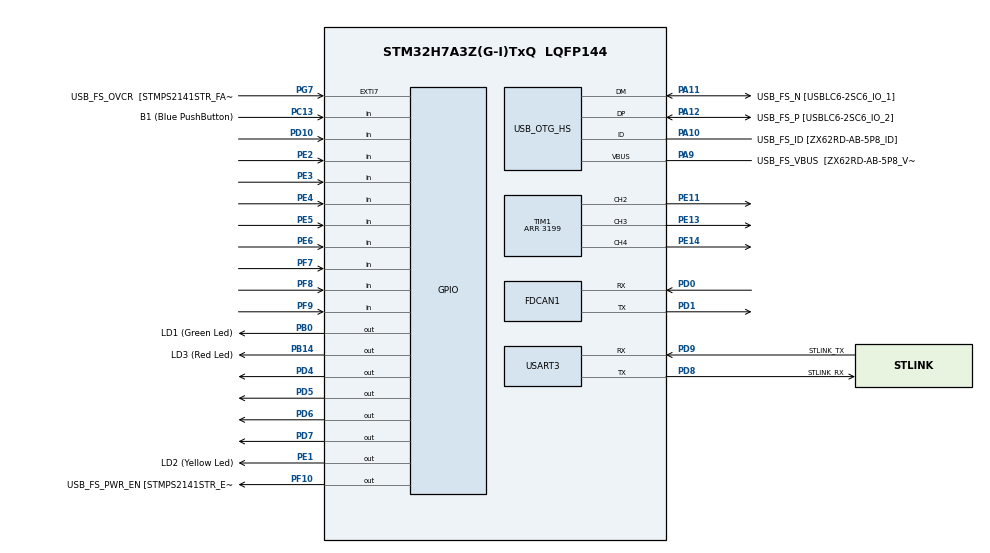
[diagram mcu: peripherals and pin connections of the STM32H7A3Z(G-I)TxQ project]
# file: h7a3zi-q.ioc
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Dma.Request0=USART3_RX
Dma.USART3_RX.0.Direction=DMA_PERIPH_TO_MEMORY
Dma.USART3_RX.0.EventEnable=DISABLE
Dma.USART3_RX.0.FIFOMode=DMA_FIFOMODE_DISABLE
Dma.USART3_RX.0.Instance=DMA1_Stream0
Dma.USART3_RX.0.MemDataAlignment=DMA_MDATAALIGN_BYTE
Dma.USART3_RX.0.MemInc=DMA_MINC_ENABLE
Dma.USART3_RX.0.Mode=DMA_CIRCULAR
Dma.USART3_RX.0.PeriphDataAlignment=DMA_PDATAALIGN_BYTE
Dma.USART3_RX.0.PeriphInc=DMA_PINC_DISABLE
Dma.USART3_RX.0.Polarity=HAL_DMAMUX_REQ_GEN_RISING
Dma.USART3_RX.0.Priority=DMA_PRIORITY_LOW
Dma.USART3_RX.0.RequestNumber=1
Dma.USART3_RX.0.SignalID=NONE
Dma.USART3_RX.0.SyncEnable=DISABLE
Dma.USART3_RX.0.SyncPolarity=HAL_DMAMUX_SYNC_NO_EVENT
Dma.USART3_RX.0.SyncRequestNumber=1
Dma.USART3_RX.0.SyncSignalID=NONE
FDCAN1.AutoRetransmission=ENABLE
FDCAN1.CalculateBaudRateNominal=1000000
FDCAN1.CalculateTimeBitNominal=1000
FDCAN1.CalculateTimeQuantumNominal=20.0
FDCAN1.DataPrescaler=2
FDCAN1.DataSyncJumpWidth=12
FDCAN1.DataTimeSeg1=12
FDCAN1.DataTimeSeg2=12
FDCAN1.ExtFiltersNbr=0
FDCAN1.FrameFormat=FDCAN_FRAME_CLASSIC
FDCAN1.NominalPrescaler=1
FDCAN1.NominalSyncJumpWidth=14
FDCAN1.NominalTimeSeg1=35
FDCAN1.NominalTimeSeg2=14
FDCAN1.RxFifo0ElmtSize=FDCAN_DATA_BYTES_8
FDCAN1.RxFifo0ElmtsNbr=32
FDCAN1.StdFiltersNbr=0
FDCAN1.TransmitPause=ENABLE
FDCAN1.TxFifoQueueElmtsNbr=32
Mcu.Family=STM32H7
Mcu.Name=STM32H7A3Z(G-I)TxQ
Mcu.Package=LQFP144
NVIC.DMA1_Stream0_IRQn=true\:0\:0\:false\:false\:true\:false\:true\:true
NVIC.FDCAN1_IT0_IRQn=true\:0\:0\:false\:false\:true\:true\:true\:true
NVIC.PriorityGroup=NVIC_PRIORITYGROUP_4
NVIC.TIM6_DAC_IRQn=true\:15\:0\:false\:false\:true\:false\:true\:true
NVIC.TimeBase=TIM6_DAC_IRQn
NVIC.TimeBaseIP=TIM6
NVIC.USART3_IRQn=true\:0\:0\:false\:false\:true\:true\:true\:true
PA10.GPIO_Label=USB_FS_ID [ZX62RD-AB-5P8_ID]
PA10.Mode=OTG/Dual-Role-Device-FS
PA10.Signal=USB_OTG_HS_ID
PA11.GPIO_Label=USB_FS_N [USBLC6-2SC6_IO_1]
PA11.Mode=OTG/Dual-Role-Device-FS
PA11.Signal=USB_OTG_HS_DM
PA12.GPIO_Label=USB_FS_P [USBLC6-2SC6_IO_2]
PA12.Mode=OTG/Dual-Role-Device-FS
PA12.Signal=USB_OTG_HS_DP
PA9.GPIO_Label=USB_FS_VBUS  [ZX62RD-AB-5P8_VBUS]
PA9.Mode=Activate_VBUS_FS
PA9.Signal=USB_OTG_HS_VBUS
PB0.GPIO_Label=LD1 (Green Led)
PB0.Signal=GPIO_Output
PB14.GPIO_Label=LD3 (Red Led)
PB14.Signal=GPIO_Output
PC13.GPIO_Label=B1 (Blue PushButton)
PC13.Signal=GPIO_Input
PC14-OSC32_IN.GPIO_Label=OSC32_IN
PC14-OSC32_IN.Mode=LSE-External-Oscillator
PC14-OSC32_IN.Signal=RCC_OSC32_IN
PC15-OSC32_OUT.GPIO_Label=OSC32_OUT
PC15-OSC32_OUT.Mode=LSE-External-Oscillator
PC15-OSC32_OUT.Signal=RCC_OSC32_OUT
PD0.Mode=FDCAN_Activate
PD0.Signal=FDCAN1_RX
PD1.Mode=FDCAN_Activate
PD1.Signal=FDCAN1_TX
PD10.GPIO_PuPd=GPIO_PULLDOWN
PD10.Signal=GPIO_Input
PD4.Signal=GPIO_Output
PD5.Signal=GPIO_Output
PD6.Signal=GPIO_Output
PD7.Signal=GPIO_Output
PD8.GPIO_Label=STLINK_RX
PD8.Mode=Asynchronous
PD8.Signal=USART3_TX
PD9.GPIO_Label=STLINK_TX
PD9.Mode=Asynchronous
PD9.Signal=USART3_RX
PE1.GPIO_Label=LD2 (Yellow Led)
PE1.Signal=GPIO_Output
PE11.GPIO_PuPd=GPIO_PULLDOWN
PE11.Signal=S_TIM1_CH2
PE13.GPIO_PuPd=GPIO_PULLDOWN
PE13.Signal=S_TIM1_CH3
PE14.GPIO_PuPd=GPIO_PULLDOWN
PE14.Signal=S_TIM1_CH4
PE2.GPIO_PuPd=GPIO_PULLDOWN
PE2.Signal=GPIO_Input
PE3.GPIO_PuPd=GPIO_PULLDOWN
PE3.Signal=GPIO_Input
PE4.GPIO_PuPd=GPIO_PULLDOWN
PE4.Signal=GPIO_Input
PE5.GPIO_PuPd=GPIO_PULLDOWN
PE5.Signal=GPIO_Input
PE6.GPIO_PuPd=GPIO_PULLDOWN
PE6.Signal=GPIO_Input
PF10.GPIO_Label=USB_FS_PWR_EN [STMPS2141STR_EN]
PF10.Signal=GPIO_Output
PF7.GPIO_PuPd=GPIO_PULLDOWN
PF7.Signal=GPIO_Input
PF8.GPIO_PuPd=GPIO_PULLDOWN
PF8.Signal=GPIO_Input
PF9.GPIO_PuPd=GPIO_PULLDOWN
PF9.Signal=GPIO_Input
PG7.GPIO_Label=USB_FS_OVCR  [STMPS2141STR_FAULT]
PG7.Signal=GPXTI7
PH0-OSC_IN.GPIO_Label=PH0-MCU
PH0-OSC_IN.Mode=HSE-External-Oscillator
PH0-OSC_IN.Signal=RCC_OSC_IN
PH1-OSC_OUT.GPIO_Label=PH1-MCU
PH1-OSC_OUT.Mode=HSE-External-Oscillator
PH1-OSC_OUT.Signal=RCC_OSC_OUT
ProjectManager.HeapSize=0x200
ProjectManager.StackSize=0x400
ProjectManager.TargetToolchain=STM32CubeIDE
RCC.ADCFreq_Value=129000000
RCC.APB1Freq_Value=64000000
RCC.APB2Freq_Value=64000000
RCC.APB3Freq_Value=64000000
RCC.APB4Freq_Value=64000000
RCC.CortexFreq_Value=64000000
RCC.DIVM1=4
RCC.DIVM3=1
RCC.DIVN1=9
RCC.DIVN3=24
RCC.DIVQ1=3
RCC.HCLKFreq_Value=64000000
RCC.HSE_VALUE=8000000
RCC.PLLFRACN=3072
RCC.PWR_Regulator_Voltage_Scale=PWR_REGULATOR_VOLTAGE_SCALE0
RCC.SYSCLKFreq_VALUE=64000000
RCC.SupplySource=PWR_DIRECT_SMPS_SUPPLY
RCC.USBCLockSelection=RCC_USBCLKSOURCE_HSI48
RCC.USBFreq_Value=48000000
SH.S_TIM1_CH2.0=TIM1_CH2,PWM Generation2 CH2
SH.S_TIM1_CH3.0=TIM1_CH3,PWM Generation3 CH3
SH.S_TIM1_CH4.0=TIM1_CH4,PWM Generation4 CH4
TIM1.Channel-PWM\ Generation2\ CH2=TIM_CHANNEL_2
TIM1.Channel-PWM\ Generation3\ CH3=TIM_CHANNEL_3
TIM1.Channel-PWM\ Generation4\ CH4=TIM_CHANNEL_4
TIM1.Period=3199
USART3.VirtualMode-Asynchronous=VM_ASYNC
VP_SYS_VS_tim6.Mode=TIM6
board=NUCLEO-H7A3ZI-Q

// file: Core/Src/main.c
/* USER CODE BEGIN Header */
/**
  ******************************************************************************
  * @file           : main.c
  * @brief          : Main program body
  ******************************************************************************
  * @attention
  *
  * Copyright (c) 2023 STMicroelectronics.
  * All rights reserved.
  *
  * This software is licensed under terms that can be found in the LICENSE file
  * in the root directory of this software component.
  * If no LICENSE file comes with this software, it is provided AS-IS.
  *
  ******************************************************************************
  */
/* USER CODE END Header */
#include "main.h"

/* USER CODE BEGIN Includes */

#include <Periph_Switch.h>
#include <Periph_UartRingBuf.h>
#include <Periph_Solenoid.h>
#include <Manager_Motor.h>
#include <Manager_HMI.h>
#include <Manager_Movement.h>
#include <Manager_Security.h>
#include <Manager_Error.h>

/* USER CODE END Includes */

FDCAN_HandleTypeDef hfdcan1;

TIM_HandleTypeDef htim1;

UART_HandleTypeDef huart3;
DMA_HandleTypeDef hdma_usart3_rx;

void SystemClock_Config(void);
static void MX_GPIO_Init(void);
static void MX_DMA_Init(void);
static void MX_USB_OTG_HS_USB_Init(void);
static void MX_FDCAN1_Init(void);
static void MX_USART3_UART_Init(void);
static void MX_TIM1_Init(void);

int main(void)
{

  /* MCU Configuration--------------------------------------------------------*/

  /* Reset of all peripherals, Initializes the Flash interface and the Systick. */
  HAL_Init();

  /* Configure the system clock */
  SystemClock_Config();

  /* Initialize all configured peripherals */
  MX_GPIO_Init();
  MX_DMA_Init();
  MX_USB_OTG_HS_USB_Init();
  MX_FDCAN1_Init();
  MX_USART3_UART_Init();
  MX_TIM1_Init();

  /* Infinite loop */
  /* USER CODE BEGIN WHILE */

    ManagerError_Init();
	ManagerMotor_Init();
	ManagerHMI_Init();
	ManagerMovement_Init();
	ManagerSecurity_Init();
	PeriphSolenoid_Init();

  while (1)
  {
	PeriphUartRingBuf_Task();
	PeriphSwitch_Task();

	ManagerMotor_Task();
	ManagerHMI_Task();
	ManagerMovement_Task();
	ManagerSecurity_Task();

    /* USER CODE END WHILE */

  }
}

void SystemClock_Config(void)
{
  RCC_OscInitTypeDef RCC_OscInitStruct = {0};
  RCC_ClkInitTypeDef RCC_ClkInitStruct = {0};

  /*AXI clock gating */
  RCC->CKGAENR = 0xFFFFFFFF;

  /** Supply configuration update enable
  */
  HAL_PWREx_ConfigSupply(PWR_DIRECT_SMPS_SUPPLY);

  /** Configure the main internal regulator output voltage
  */
  __HAL_PWR_VOLTAGESCALING_CONFIG(PWR_REGULATOR_VOLTAGE_SCALE0);

  while(!__HAL_PWR_GET_FLAG(PWR_FLAG_VOSRDY)) {}

  /** Initializes the RCC Oscillators according to the specified parameters
  * in the RCC_OscInitTypeDef structure.
  */
  RCC_OscInitStruct.OscillatorType = RCC_OSCILLATORTYPE_HSI48|RCC_OSCILLATORTYPE_HSI;
  RCC_OscInitStruct.HSIState = RCC_HSI_DIV1;
  RCC_OscInitStruct.HSICalibrationValue = 64;
  RCC_OscInitStruct.HSI48State = RCC_HSI48_ON;
  RCC_OscInitStruct.PLL.PLLState = RCC_PLL_ON;
  RCC_OscInitStruct.PLL.PLLSource = RCC_PLLSOURCE_HSI;
  RCC_OscInitStruct.PLL.PLLM = 4;
  RCC_OscInitStruct.PLL.PLLN = 9;
  RCC_OscInitStruct.PLL.PLLP = 2;
  RCC_OscInitStruct.PLL.PLLQ = 3;
  RCC_OscInitStruct.PLL.PLLR = 2;
  RCC_OscInitStruct.PLL.PLLRGE = RCC_PLL1VCIRANGE_3;
  RCC_OscInitStruct.PLL.PLLVCOSEL = RCC_PLL1VCOWIDE;
  RCC_OscInitStruct.PLL.PLLFRACN = 3072;
  if (HAL_RCC_OscConfig(&RCC_OscInitStruct) != HAL_OK)
  {
    Error_Handler();
  }

  /** Initializes the CPU, AHB and APB buses clocks
  */
  RCC_ClkInitStruct.ClockType = RCC_CLOCKTYPE_HCLK|RCC_CLOCKTYPE_SYSCLK
                              |RCC_CLOCKTYPE_PCLK1|RCC_CLOCKTYPE_PCLK2
                              |RCC_CLOCKTYPE_D3PCLK1|RCC_CLOCKTYPE_D1PCLK1;
  RCC_ClkInitStruct.SYSCLKSource = RCC_SYSCLKSOURCE_HSI;
  RCC_ClkInitStruct.SYSCLKDivider = RCC_SYSCLK_DIV1;
  RCC_ClkInitStruct.AHBCLKDivider = RCC_HCLK_DIV1;
  RCC_ClkInitStruct.APB3CLKDivider = RCC_APB3_DIV1;
  RCC_ClkInitStruct.APB1CLKDivider = RCC_APB1_DIV1;
  RCC_ClkInitStruct.APB2CLKDivider = RCC_APB2_DIV1;
  RCC_ClkInitStruct.APB4CLKDivider = RCC_APB4_DIV1;

  if (HAL_RCC_ClockConfig(&RCC_ClkInitStruct, FLASH_LATENCY_1) != HAL_OK)
  {
    Error_Handler();
  }
}

static void MX_FDCAN1_Init(void)
{

  hfdcan1.Instance = FDCAN1;
  hfdcan1.Init.FrameFormat = FDCAN_FRAME_CLASSIC;
  hfdcan1.Init.Mode = FDCAN_MODE_NORMAL;
  hfdcan1.Init.AutoRetransmission = ENABLE;
  hfdcan1.Init.TransmitPause = ENABLE;
  hfdcan1.Init.ProtocolException = DISABLE;
  hfdcan1.Init.NominalPrescaler = 1;
  hfdcan1.Init.NominalSyncJumpWidth = 14;
  hfdcan1.Init.NominalTimeSeg1 = 35;
  hfdcan1.Init.NominalTimeSeg2 = 14;
  hfdcan1.Init.DataPrescaler = 2;
  hfdcan1.Init.DataSyncJumpWidth = 12;
  hfdcan1.Init.DataTimeSeg1 = 12;
  hfdcan1.Init.DataTimeSeg2 = 12;
  hfdcan1.Init.MessageRAMOffset = 0;
  hfdcan1.Init.StdFiltersNbr = 0;
  hfdcan1.Init.ExtFiltersNbr = 0;
  hfdcan1.Init.RxFifo0ElmtsNbr = 32;
  hfdcan1.Init.RxFifo0ElmtSize = FDCAN_DATA_BYTES_8;
  hfdcan1.Init.RxFifo1ElmtsNbr = 0;
  hfdcan1.Init.RxFifo1ElmtSize = FDCAN_DATA_BYTES_8;
  hfdcan1.Init.RxBuffersNbr = 0;
  hfdcan1.Init.RxBufferSize = FDCAN_DATA_BYTES_8;
  hfdcan1.Init.TxEventsNbr = 0;
  hfdcan1.Init.TxBuffersNbr = 0;
  hfdcan1.Init.TxFifoQueueElmtsNbr = 32;
  hfdcan1.Init.TxFifoQueueMode = FDCAN_TX_FIFO_OPERATION;
  hfdcan1.Init.TxElmtSize = FDCAN_DATA_BYTES_8;
  if (HAL_FDCAN_Init(&hfdcan1) != HAL_OK)
  {
    Error_Handler();
  }

}

static void MX_TIM1_Init(void)
{

  TIM_MasterConfigTypeDef sMasterConfig = {0};
  TIM_OC_InitTypeDef sConfigOC = {0};
  TIM_BreakDeadTimeConfigTypeDef sBreakDeadTimeConfig = {0};

  htim1.Instance = TIM1;
  htim1.Init.Prescaler = 0;
  htim1.Init.CounterMode = TIM_COUNTERMODE_UP;
  htim1.Init.Period = 3199;
  htim1.Init.ClockDivision = TIM_CLOCKDIVISION_DIV1;
  htim1.Init.RepetitionCounter = 0;
  htim1.Init.AutoReloadPreload = TIM_AUTORELOAD_PRELOAD_DISABLE;
  if (HAL_TIM_PWM_Init(&htim1) != HAL_OK)
  {
    Error_Handler();
  }
  sMasterConfig.MasterOutputTrigger = TIM_TRGO_RESET;
  sMasterConfig.MasterOutputTrigger2 = TIM_TRGO2_RESET;
  sMasterConfig.MasterSlaveMode = TIM_MASTERSLAVEMODE_DISABLE;
  if (HAL_TIMEx_MasterConfigSynchronization(&htim1, &sMasterConfig) != HAL_OK)
  {
    Error_Handler();
  }
  sConfigOC.OCMode = TIM_OCMODE_PWM1;
  sConfigOC.Pulse = 0;
  sConfigOC.OCPolarity = TIM_OCPOLARITY_HIGH;
  sConfigOC.OCNPolarity = TIM_OCNPOLARITY_HIGH;
  sConfigOC.OCFastMode = TIM_OCFAST_DISABLE;
  sConfigOC.OCIdleState = TIM_OCIDLESTATE_RESET;
  sConfigOC.OCNIdleState = TIM_OCNIDLESTATE_RESET;
  if (HAL_TIM_PWM_ConfigChannel(&htim1, &sConfigOC, TIM_CHANNEL_2) != HAL_OK)
  {
    Error_Handler();
  }
  if (HAL_TIM_PWM_ConfigChannel(&htim1, &sConfigOC, TIM_CHANNEL_3) != HAL_OK)
  {
    Error_Handler();
  }
  if (HAL_TIM_PWM_ConfigChannel(&htim1, &sConfigOC, TIM_CHANNEL_4) != HAL_OK)
  {
    Error_Handler();
  }
  sBreakDeadTimeConfig.OffStateRunMode = TIM_OSSR_DISABLE;
  sBreakDeadTimeConfig.OffStateIDLEMode = TIM_OSSI_DISABLE;
  sBreakDeadTimeConfig.LockLevel = TIM_LOCKLEVEL_OFF;
  sBreakDeadTimeConfig.DeadTime = 0;
  sBreakDeadTimeConfig.BreakState = TIM_BREAK_DISABLE;
  sBreakDeadTimeConfig.BreakPolarity = TIM_BREAKPOLARITY_HIGH;
  sBreakDeadTimeConfig.BreakFilter = 0;
  sBreakDeadTimeConfig.Break2State = TIM_BREAK2_DISABLE;
  sBreakDeadTimeConfig.Break2Polarity = TIM_BREAK2POLARITY_HIGH;
  sBreakDeadTimeConfig.Break2Filter = 0;
  sBreakDeadTimeConfig.AutomaticOutput = TIM_AUTOMATICOUTPUT_DISABLE;
  if (HAL_TIMEx_ConfigBreakDeadTime(&htim1, &sBreakDeadTimeConfig) != HAL_OK)
  {
    Error_Handler();
  }
  HAL_TIM_MspPostInit(&htim1);

}

static void MX_USART3_UART_Init(void)
{

  huart3.Instance = USART3;
  huart3.Init.BaudRate = 115200;
  huart3.Init.WordLength = UART_WORDLENGTH_8B;
  huart3.Init.StopBits = UART_STOPBITS_1;
  huart3.Init.Parity = UART_PARITY_NONE;
  huart3.Init.Mode = UART_MODE_TX_RX;
  huart3.Init.HwFlowCtl = UART_HWCONTROL_NONE;
  huart3.Init.OverSampling = UART_OVERSAMPLING_16;
  huart3.Init.OneBitSampling = UART_ONE_BIT_SAMPLE_DISABLE;
  huart3.Init.ClockPrescaler = UART_PRESCALER_DIV1;
  huart3.AdvancedInit.AdvFeatureInit = UART_ADVFEATURE_NO_INIT;
  if (HAL_UART_Init(&huart3) != HAL_OK)
  {
    Error_Handler();
  }
  if (HAL_UARTEx_SetTxFifoThreshold(&huart3, UART_TXFIFO_THRESHOLD_1_8) != HAL_OK)
  {
    Error_Handler();
  }
  if (HAL_UARTEx_SetRxFifoThreshold(&huart3, UART_RXFIFO_THRESHOLD_1_8) != HAL_OK)
  {
    Error_Handler();
  }
  if (HAL_UARTEx_DisableFifoMode(&huart3) != HAL_OK)
  {
    Error_Handler();
  }

}

static void MX_USB_OTG_HS_USB_Init(void)
{

}

static void MX_DMA_Init(void)
{

  /* DMA controller clock enable */
  __HAL_RCC_DMA1_CLK_ENABLE();

  /* DMA interrupt init */
  /* DMA1_Stream0_IRQn interrupt configuration */
  HAL_NVIC_SetPriority(DMA1_Stream0_IRQn, 0, 0);
  HAL_NVIC_EnableIRQ(DMA1_Stream0_IRQn);

}

static void MX_GPIO_Init(void)
{
  GPIO_InitTypeDef GPIO_InitStruct = {0};

  /* GPIO Ports Clock Enable */
  __HAL_RCC_GPIOE_CLK_ENABLE();
  __HAL_RCC_GPIOC_CLK_ENABLE();
  __HAL_RCC_GPIOF_CLK_ENABLE();
  __HAL_RCC_GPIOH_CLK_ENABLE();
  __HAL_RCC_GPIOB_CLK_ENABLE();
  __HAL_RCC_GPIOD_CLK_ENABLE();
  __HAL_RCC_GPIOG_CLK_ENABLE();
  __HAL_RCC_GPIOA_CLK_ENABLE();

  /*Configure GPIO pin Output Level */
  HAL_GPIO_WritePin(USB_FS_PWR_EN_GPIO_Port, USB_FS_PWR_EN_Pin, GPIO_PIN_RESET);

  /*Configure GPIO pin Output Level */
  HAL_GPIO_WritePin(GPIOB, LD1_Pin|LD3_Pin, GPIO_PIN_RESET);

  /*Configure GPIO pin Output Level */
  HAL_GPIO_WritePin(GPIOD, GPIO_PIN_2|GPIO_PIN_3|GPIO_PIN_4|GPIO_PIN_5
                          |GPIO_PIN_6|GPIO_PIN_7, GPIO_PIN_RESET);

  /*Configure GPIO pin Output Level */
  HAL_GPIO_WritePin(LD2_GPIO_Port, LD2_Pin, GPIO_PIN_RESET);

  /*Configure GPIO pins : PE2 PE3 PE4 PE5
                           PE6 */
  GPIO_InitStruct.Pin = GPIO_PIN_2|GPIO_PIN_3|GPIO_PIN_4|GPIO_PIN_5
                          |GPIO_PIN_6;
  GPIO_InitStruct.Mode = GPIO_MODE_INPUT;
  GPIO_InitStruct.Pull = GPIO_PULLDOWN;
  HAL_GPIO_Init(GPIOE, &GPIO_InitStruct);

  /*Configure GPIO pin : B1_Pin */
  GPIO_InitStruct.Pin = B1_Pin;
  GPIO_InitStruct.Mode = GPIO_MODE_INPUT;
  GPIO_InitStruct.Pull = GPIO_NOPULL;
  HAL_GPIO_Init(B1_GPIO_Port, &GPIO_InitStruct);

  /*Configure GPIO pins : PF7 PF8 PF9 */
  GPIO_InitStruct.Pin = GPIO_PIN_7|GPIO_PIN_8|GPIO_PIN_9;
  GPIO_InitStruct.Mode = GPIO_MODE_INPUT;
  GPIO_InitStruct.Pull = GPIO_PULLDOWN;
  HAL_GPIO_Init(GPIOF, &GPIO_InitStruct);

  /*Configure GPIO pin : USB_FS_PWR_EN_Pin */
  GPIO_InitStruct.Pin = USB_FS_PWR_EN_Pin;
  GPIO_InitStruct.Mode = GPIO_MODE_OUTPUT_PP;
  GPIO_InitStruct.Pull = GPIO_NOPULL;
  GPIO_InitStruct.Speed = GPIO_SPEED_FREQ_LOW;
  HAL_GPIO_Init(USB_FS_PWR_EN_GPIO_Port, &GPIO_InitStruct);

  /*Configure GPIO pins : LD1_Pin LD3_Pin */
  GPIO_InitStruct.Pin = LD1_Pin|LD3_Pin;
  GPIO_InitStruct.Mode = GPIO_MODE_OUTPUT_PP;
  GPIO_InitStruct.Pull = GPIO_NOPULL;
  GPIO_InitStruct.Speed = GPIO_SPEED_FREQ_LOW;
  HAL_GPIO_Init(GPIOB, &GPIO_InitStruct);

  /*Configure GPIO pin : PD10 */
  GPIO_InitStruct.Pin = GPIO_PIN_10;
  GPIO_InitStruct.Mode = GPIO_MODE_INPUT;
  GPIO_InitStruct.Pull = GPIO_PULLDOWN;
  HAL_GPIO_Init(GPIOD, &GPIO_InitStruct);

  /*Configure GPIO pin : USB_FS_OVCR_Pin */
  GPIO_InitStruct.Pin = USB_FS_OVCR_Pin;
  GPIO_InitStruct.Mode = GPIO_MODE_IT_RISING;
  GPIO_InitStruct.Pull = GPIO_NOPULL;
  HAL_GPIO_Init(USB_FS_OVCR_GPIO_Port, &GPIO_InitStruct);

  /*Configure GPIO pin : USB_FS_VBUS_Pin */
  GPIO_InitStruct.Pin = USB_FS_VBUS_Pin;
  GPIO_InitStruct.Mode = GPIO_MODE_INPUT;
  GPIO_InitStruct.Pull = GPIO_NOPULL;
  HAL_GPIO_Init(USB_FS_VBUS_GPIO_Port, &GPIO_InitStruct);

  /*Configure GPIO pin : USB_FS_ID_Pin */
  GPIO_InitStruct.Pin = USB_FS_ID_Pin;
  GPIO_InitStruct.Mode = GPIO_MODE_AF_PP;
  GPIO_InitStruct.Pull = GPIO_NOPULL;
  GPIO_InitStruct.Speed = GPIO_SPEED_FREQ_LOW;
  GPIO_InitStruct.Alternate = GPIO_AF10_OTG1_HS;
  HAL_GPIO_Init(USB_FS_ID_GPIO_Port, &GPIO_InitStruct);

  /*Configure GPIO pins : USB_FS_N_Pin USB_FS_P_Pin */
  GPIO_InitStruct.Pin = USB_FS_N_Pin|USB_FS_P_Pin;
  GPIO_InitStruct.Mode = GPIO_MODE_AF_PP;
  GPIO_InitStruct.Pull = GPIO_NOPULL;
  GPIO_InitStruct.Speed = GPIO_SPEED_FREQ_LOW;
  HAL_GPIO_Init(GPIOA, &GPIO_InitStruct);

  /*Configure GPIO pins : PD2 PD3 PD4 PD5
                           PD6 PD7 */
  GPIO_InitStruct.Pin = GPIO_PIN_2|GPIO_PIN_3|GPIO_PIN_4|GPIO_PIN_5
                          |GPIO_PIN_6|GPIO_PIN_7;
  GPIO_InitStruct.Mode = GPIO_MODE_OUTPUT_PP;
  GPIO_InitStruct.Pull = GPIO_PULLDOWN;
  GPIO_InitStruct.Speed = GPIO_SPEED_FREQ_LOW;
  HAL_GPIO_Init(GPIOD, &GPIO_InitStruct);

  /*Configure GPIO pin : LD2_Pin */
  GPIO_InitStruct.Pin = LD2_Pin;
  GPIO_InitStruct.Mode = GPIO_MODE_OUTPUT_PP;
  GPIO_InitStruct.Pull = GPIO_NOPULL;
  GPIO_InitStruct.Speed = GPIO_SPEED_FREQ_LOW;
  HAL_GPIO_Init(LD2_GPIO_Port, &GPIO_InitStruct);

}

void HAL_TIM_PeriodElapsedCallback(TIM_HandleTypeDef *htim)
{
  if (htim->Instance == TIM6) {
    HAL_IncTick();
  }
}

void Error_Handler(void)
{
  __disable_irq();
  while (1)
  {
  }
}
